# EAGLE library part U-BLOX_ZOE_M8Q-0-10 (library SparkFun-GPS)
u-blox ZOE-M8Q-0-10 u-blox ZOE-M8 standard precision GNSS SiP (System in Package) modules feature the high performance u-blox M8 GNSS engine. ZOE-M8’s ultra-miniature form factor integrates a complete GNSS receiver including SAW filter, LNA and TCXO. Handles all GNSS systems and can simulatenously use up to three of them, with accuracy ranging from 2.5m to 4m. GPS GLONASS BeiDou Galileo This can be corrected with the SBAS or QZSS augmentation systems.

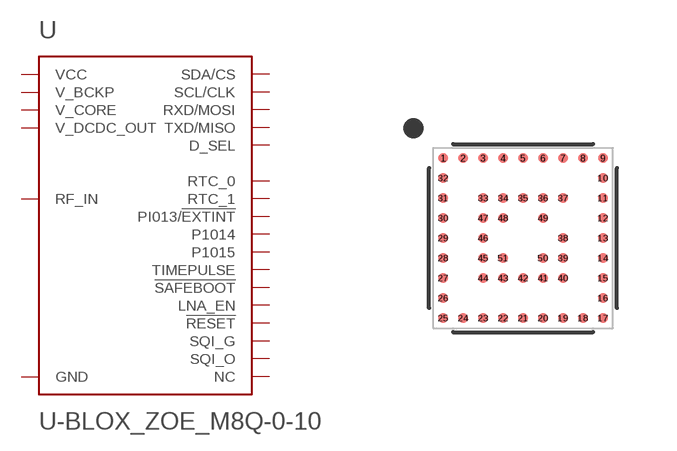
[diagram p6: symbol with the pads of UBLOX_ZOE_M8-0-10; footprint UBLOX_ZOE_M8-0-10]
Designator prefix U

## U-BLOX_ZOE_M8Q-0-10 (PROD_ID: IC-14251)  [UBLOX_ZOE_M8-0-10]
1  GND  pwr
2  SDA/CS
3  GND  pwr
4  RF_IN
5  GND  pwr
6  NC  nc
7  GND  pwr
8  GND  pwr
9  GND  pwr
10  GND  pwr
11  GND  pwr
12  GND  pwr
13  NC  nc
14  NC  nc
15  NC  nc
16  V_BCKP  pwr
17  GND  pwr
18  RTC_0
19  RTC_1
20  !RESET
21  TXD/MISO
22  RXD/MOSI
23  GND  pwr
24  VCC  pwr
25  VCC  pwr
26  V_DCDC_OUT  pwr
27  V_CORE  pwr
28  NC  nc
29  SQI_G
30  SQI_O  nc
31  SQI_G
32  SCL/CLK
33  TIMEPULSE
34  !SAFEBOOT
35  LNA_EN
36  P1015
37  GND  pwr
38  GND  pwr
39  GND  pwr
40  GND  pwr
41  GND  pwr
42  NC  nc
43  PI013/!EXTINT
44  GND  pwr
45  SQI_O  nc
46  SQI_G
47  SQI_G
48  D_SEL
49  GND  pwr
50  P1014
51  NC  nc

## Footprint UBLOX_ZOE_M8-0-10 (pad centres in mm)
u-blox ZOE-M8Q-0-10 The ZOE-M8G and ZOE-M8Q are u-blox’s super small, highly integrated GNSS SiP (System in Package) modules based on the high performing u-blox M8 concurrent positioning engine. The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
smd 0.25 x 0.25: 1 -1.996,2.004; 2 -1.496,2.004; 3 -0.996,2.004; 4 -0.496,2.004; 5 0.004,2.004; 6 0.504,2.004; 7 1.004,2.004; 8 1.504,2.004; 9 2.004,2.004; 10 2.004,1.504; 11 2.004,1.004; 12 2.004,0.504; 13 2.004,0.004; 14 2.004,-0.496; 15 2.004,-0.996; 16 2.004,-1.496; 17 2.004,-1.996; 18 1.504,-1.996; 19 1.004,-1.996; 20 0.504,-1.996; 21 0.004,-1.996; 22 -0.496,-1.996; 23 -0.996,-1.996; 24 -1.496,-1.996; 25 -1.996,-1.996; 26 -1.996,-1.496; 27 -1.996,-0.996; 28 -1.996,-0.496; 29 -1.996,0.004; 30 -1.996,0.504; 31 -1.996,1.004; 32 -1.996,1.504; 33 -0.996,1.004; 34 -0.496,1.004; 35 0.004,1.004; 36 0.504,1.004; 37 1.004,1.004; 38 1.004,0.004; 39 1.004,-0.496; 40 1.004,-0.996; 41 0.504,-0.996; 42 0.004,-0.996; 43 -0.496,-0.996; 44 -0.996,-0.996; 45 -0.996,-0.496; 46 -0.996,0.004; 47 -0.996,0.504; 48 -0.496,0.504; 49 0.504,0.504; 50 0.504,-0.496; 51 -0.496,-0.496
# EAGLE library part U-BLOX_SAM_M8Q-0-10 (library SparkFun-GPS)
u-blox SAM-M8Q The u-blox concurrent SAM-M8Q GNSS patch antenna module benefits from the exceptional performance of the u-blox M8 multi-GNSS engine. The SAM-M8Q module offers high sensitivity and minimal acquisition times in an ultra compact form factor. The SAM-M8Q module utilizes concurrent reception of up to three GNSS systems (GPS/Galileo and GLONASS), recognizes multiple constellations simultaneously and provides outstanding positioning accuracy in scenarios where urban canyon or weak signals are involved. For even better and faster positioning improvement, the SAM-M8Q supports augmentation of QZSS, GAGAN and IMES together with WAAS, EGNOS, MSAS. The SAM-M8Q also supports message integrity protection, geofencing, and spoofing detection with configurable interface settings to easily fit to customer applications.

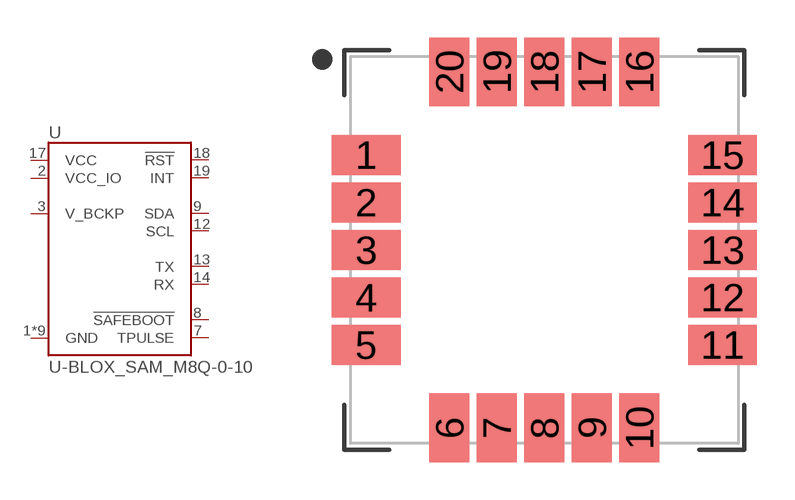
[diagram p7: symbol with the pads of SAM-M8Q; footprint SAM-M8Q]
Designator prefix U

## U-BLOX_SAM_M8Q-0-10 (PROD_ID: IC-14070)  [SAM-M8Q]
1  GND
2  VCC_IO
3  V_BCKP
4  GND
5  GND
6  GND
7  TPULSE
8  !SAFEBOOT
9  SDA
10  GND
11  GND
12  SCL
13  TX
14  RX
15  GND
16  GND
17  VCC
18  !RST
19  INT
20  GND

## Footprint SAM-M8Q (pad centres in mm)
SAM-M8Q-0-10 Physcial Characteristics 15x15x6.3mm Module is a Chip Antenna/GPS Unit combined
smd 2.75 x 1.6: 1 -7.125,3.8; 2 -7.125,1.9; 3 -7.125,0; 4 -7.125,-1.9; 5 -7.125,-3.8; 11 7.125,-3.8; 12 7.125,-1.9; 13 7.125,0; 14 7.125,1.9; 15 7.125,3.8
smd 1.6 x 2.75: 6 -3.8,-7.125; 7 -1.9,-7.125; 8 0,-7.125; 9 1.9,-7.125; 10 3.8,-7.125; 16 3.8,7.125; 17 1.9,7.125; 18 0,7.125; 19 -1.9,7.125; 20 -3.8,7.125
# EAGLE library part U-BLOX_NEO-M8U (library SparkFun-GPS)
u-blox NEO-M8U The NEO-M8U module introduces u-blox’s Untethered Dead Reckoning (UDR) technology, which provides continuous navigation without requiring speed information from the vehicle. This innovative technology brings the benefits of dead reckoning to installations previously restricted to using GNSS alone, and significantly reduces the cost of installation for after-market dead reckoning applications. The strength of UDR is particularly apparent under poor signal conditions, where it brings continuous positioning in urban environments, even to devices with antennas installed within the vehicle. Useful positioning performance is also available during complete signal loss, for example in parking garages and short tunnels. With UDR, positioning starts as soon as power is applied to the module, before the first GNSS fix is available. The NEO-M8U may be installed in any position within the vehicle without configuration. In addition to its freedom from any electrical connection to the vehicle, the on-board accelerometer and gyroscope sensors result in a fully self-contained solution, perfect for rapid product development with reliable and consistent performance.

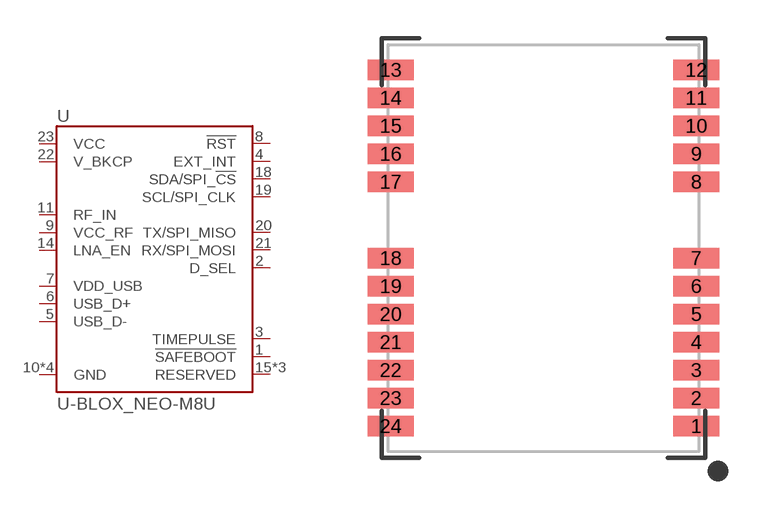
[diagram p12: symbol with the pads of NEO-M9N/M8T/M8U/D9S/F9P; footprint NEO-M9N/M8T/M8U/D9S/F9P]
Designator prefix U

## U-BLOX_NEO-M8U (PROD_ID: IC-14850)  [NEO-M9N/M8T/M8U/D9S/F9P]
1  !SAFEBOOT!
2  D_SEL
3  TIMEPULSE
4  EXT_INT
5  USB_D-
6  USB_D+
7  VDD_USB
8  !RST
9  VCC_RF
10  GND
11  RF_IN
12  GND
13  GND
14  LNA_EN
15  RESERVED  nc
16  RESERVED  nc
17  RESERVED  nc
18  SDA/SPI_!CS!
19  SCL/SPI_CLK
20  TX/SPI_MISO
21  RX/SPI_MOSI
22  V_BKCP
23  VCC
24  GND

## Footprint NEO-M9N/M8T/M8U/D9S/F9P (pad centres in mm)
u-blox NEO-M9N/M8T/M8U/D9S Module Mechanical Specifications Overall: 12.2mm x 16.0mm Pad Pitch: 1.1mm Pad Width: .8mm Pad Length: .9mm Number of Pins: 24
smd 1.8 x 0.8: 1 6,-7; 2 6,-5.9; 3 6,-4.8; 4 6,-3.7; 5 6,-2.6; 6 6,-1.5; 7 6,-0.4; 8 6,2.6; 9 6,3.7; 10 6,4.8; 11 6,5.9; 12 6,7; 13 -6,7; 14 -6,5.9; 15 -6,4.8; 16 -6,3.7; 17 -6,2.6; 18 -6,-0.4; 19 -6,-1.5; 20 -6,-2.6; 21 -6,-3.7; 22 -6,-4.8; 23 -6,-5.9; 24 -6,-7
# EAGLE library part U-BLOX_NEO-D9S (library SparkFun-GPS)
u-blox NEO-D9S The NEO-D9S can receive the data stream of a GNSS correction service, broadcast via satellite L band and compliant to the specification the product is designed for. Integrated with a high precision GNSS receiver, such as from the u-blox F9 platform, it enables the positioning system to reach down to centimeter-level accuracy.

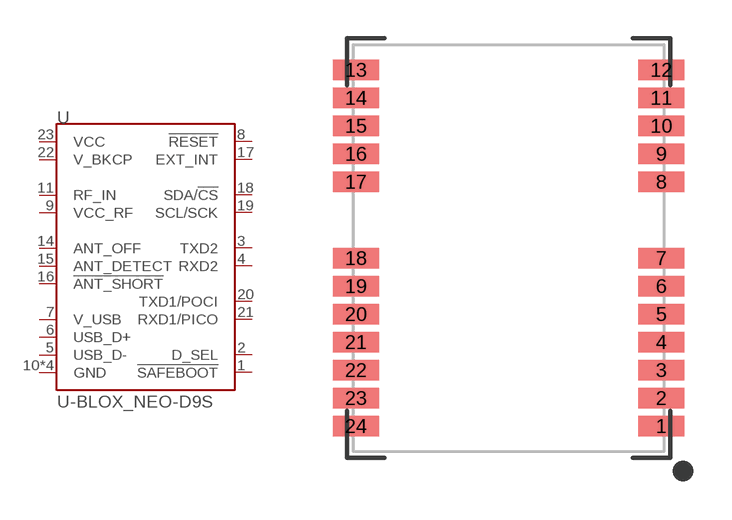
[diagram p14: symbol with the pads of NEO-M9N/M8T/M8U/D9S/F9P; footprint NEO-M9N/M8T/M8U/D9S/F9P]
Designator prefix U

## U-BLOX_NEO-D9S-00B (PROD_ID: IC-16579)  [NEO-M9N/M8T/M8U/D9S/F9P]
1  !SAFEBOOT!  in
2  D_SEL  in
3  TXD2  out
4  RXD2  in
5  USB_D-
6  USB_D+
7  V_USB  pwr
8  !RESET!  in
9  VCC_RF  out
10  GND  pwr
11  RF_IN  in
12  GND  pwr
13  GND  pwr
14  ANT_OFF  out
15  ANT_DETECT  in
16  !ANT_SHORT!  out
17  EXT_INT  in
18  SDA/!CS!
19  SCL/SCK
20  TXD1/POCI  out
21  RXD1/PICO  in
22  V_BKCP  pwr
23  VCC  pwr
24  GND  pwr

## Footprint NEO-M9N/M8T/M8U/D9S/F9P (pad centres in mm)
u-blox NEO-M9N/M8T/M8U/D9S Module Mechanical Specifications Overall: 12.2mm x 16.0mm Pad Pitch: 1.1mm Pad Width: .8mm Pad Length: .9mm Number of Pins: 24
smd 1.8 x 0.8: 1 6,-7; 2 6,-5.9; 3 6,-4.8; 4 6,-3.7; 5 6,-2.6; 6 6,-1.5; 7 6,-0.4; 8 6,2.6; 9 6,3.7; 10 6,4.8; 11 6,5.9; 12 6,7; 13 -6,7; 14 -6,5.9; 15 -6,4.8; 16 -6,3.7; 17 -6,2.6; 18 -6,-0.4; 19 -6,-1.5; 20 -6,-2.6; 21 -6,-3.7; 22 -6,-4.8; 23 -6,-5.9; 24 -6,-7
